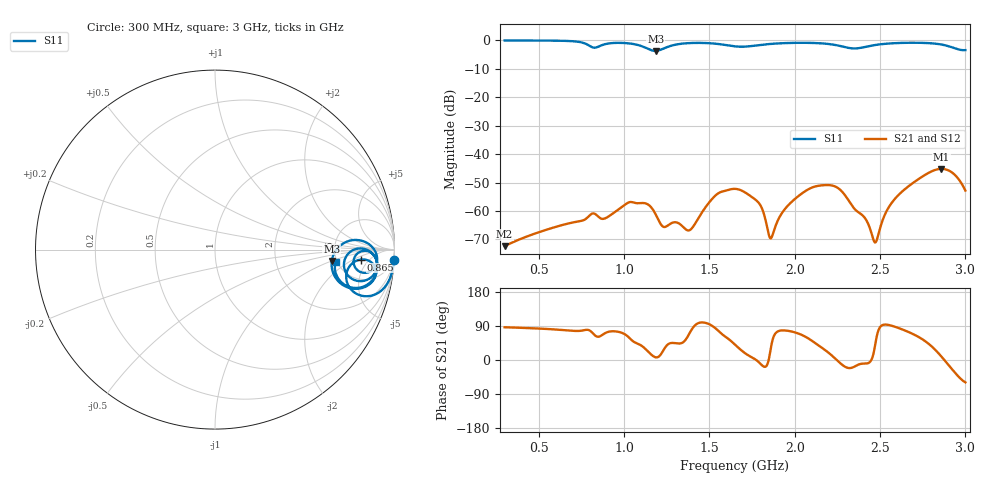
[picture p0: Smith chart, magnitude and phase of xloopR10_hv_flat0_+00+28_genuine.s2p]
! xloopR10_hv_flat0_+00+28_genuine, gap C 0.80 pF
! simulated by sim/fixtures_fdtd.py (S12 = S21, S22 not computed)
# HZ S RI R 50
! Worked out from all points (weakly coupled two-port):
!   541 points, 300 MHz to 3 GHz, reference 50 ohm
!   highest |S21| = -45.18 dB at 2.86 GHz (marker M1); lowest = -72.4 dB at 300 MHz (marker M2)
!   lowest |S11| = -3.7 dB at 1.185 GHz (marker M3), VSWR 4.78, Z = 227 - j50.4 ohm
!   |S11| at or under -10 dB: nowhere
!   |S22| runs from - to - dB; largest |S21 - S12| = 0
!   S11 on the Smith chart (normalised r, x): 300 MHz: 1, -33; 865 MHz: 8.81, -2.89; 3 GHz: 4.85, -1.20
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3e8  0.9972 -0.0596  1.52e-05 0.00024  1.52e-05 0.00024  0 0
7.5e8  0.8897 -0.2508  0.000147 0.000653  0.000147 0.000653  0 0
8.15e8  0.7344 -0.1793  0.000286 0.000856  0.000286 0.000856  0 0
8.65e8  0.8124 -0.0553  0.000322 0.000661  0.000322 0.000661  0 0
1.04e9  0.8564 -0.1965  0.00084 0.00117  0.00084 0.00117  0 0
1.135e9  0.6992 -0.1876  0.0012 0.000559  0.0012 0.000559  0 0
1.185e9  0.6508 -0.0635  0.000867 0.000108  0.000867 0.000108  0 0
1.2e9  0.6632 -0.0224  0.000703 0.0001  0.000703 0.0001  0 0
1.385e9  0.8984 -0.0233  0.000145 0.000438  0.000145 0.000438  0 0
1.535e9  0.868 -0.1203  0.000197 0.00186  0.000197 0.00186  0 0
1.65e9  0.7808 -0.0994  0.00186 0.00159  0.00186 0.00159  0 0
1.79e9  0.827 -0.00704  0.00137 -0.000143  0.00137 -0.000143  0 0
1.86e9  0.8687 -0.0164  0.000281 0.00017  0.000281 0.00017  0 0
1.945e9  0.8966 -0.048  0.000232 0.00108  0.000232 0.00108  0 0
2.1e9  0.8957 -0.121  0.00162 0.002  0.00162 0.002  0 0
2.265e9  0.7821 -0.1714  0.00236 -0.000322  0.00236 -0.000322  0 0
2.415e9  0.7716 -0.00146  0.000715 -0.000119  0.000715 -0.000119  0 0
2.47e9  0.8297 0.00441  0.000224 0.000166  0.000224 0.000166  0 0
2.55e9  0.8813 -0.0275  -5.01e-05 0.00115  -5.01e-05 0.00115  0 0
2.685e9  0.9047 -0.1024  0.00102 0.00282  0.00102 0.00282  0 0
2.86e9  0.8209 -0.2083  0.00544 0.000848  0.00544 0.000848  0 0
3e9  0.672 -0.067  0.00118 -0.00196  0.00118 -0.00196  0 0
